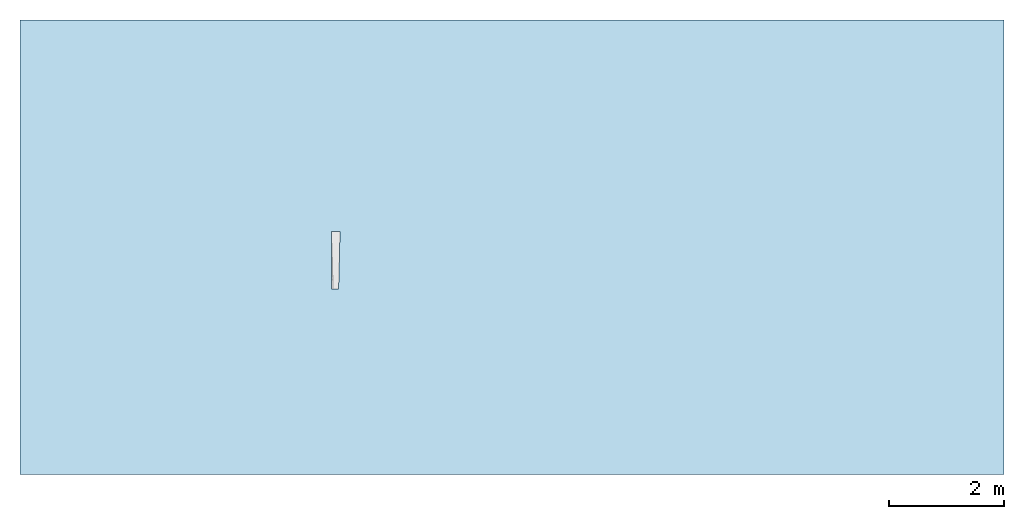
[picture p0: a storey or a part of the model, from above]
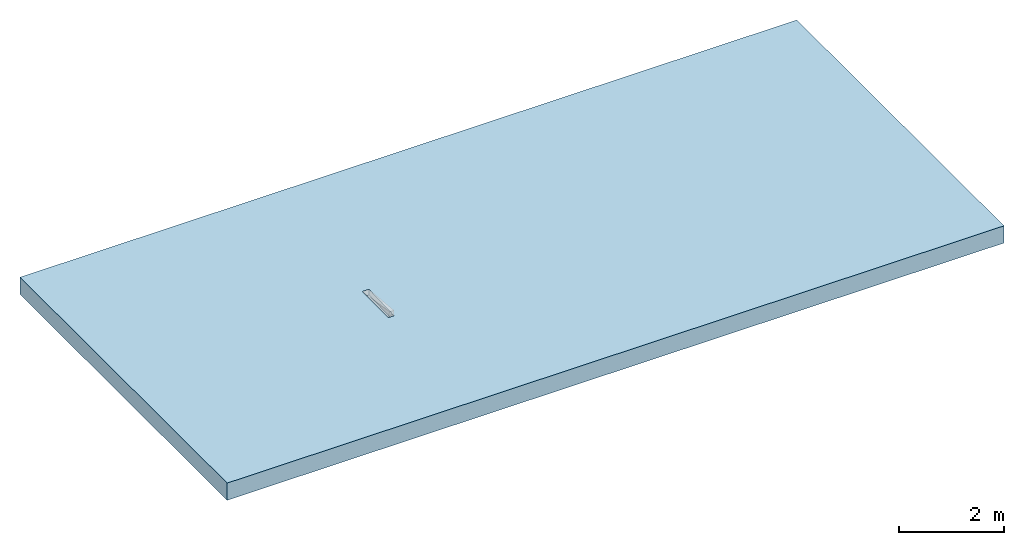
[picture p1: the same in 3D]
Properties of the parts of a building model (IFC2X3)

# File
Description: ViewDefinition [CoordinationView]
File name: 7957 - RH drop kerb - 1000mm LG.ifc
Time: 2013-08-30T17:42:58
Written by: Autodesk Revit 2013
Made in: 20120221_2030(x64)

# IfcProject, Project Number
LongName: Project Name; Phase: Project Status

# IfcSite, Default
RefLatitude: 42, 21, 30, 344238; RefLongitude: -71, -3, -35, -194702; RefElevation: 0 mm

# IfcBuilding
Pset_BuildingCommon - NumberOfStoreys: 1
Other - Project Number: Project Number; Project Status: Project Status; Client Name: Owner; Project Issue Date: Issue Date; Project Address: ## Street City, State Zip; Project Name: Project Name

# IfcBuildingStorey, Level 1
LongName: Level 1; Elevation: 0 mm
Constraints - Elevation Base: 0; Elevation: 0 mm
Graphics - Symbol: M_Level Head - Circle: M_Level Head - Circle; Line Pattern: Center; Line Weight: 1; Symbol at End 2 Default: yes; Color: 0; Symbol at End 1 Default: no
Identity Data - Name: Level 1; Structural: no; Building Story: yes
Dimensions - Computation Height: 0 mm

# IfcBuildingElementProxy: 7957 - RH drop kerb - 1000mm LG, Civil-Drainage-Channel-ACO-KerbDrain-HB255:7957 - RH drop kerb - 1000mm LG:7957 - RH drop kerb - 1000mm LG:754467
In: Level 1
Material: ACO Polymer Concrete.
Phasing - Phase Created: New Construction
Constraints - Moves With Nearby Elements: no; Level: Level: Level 1
Dimensions - Volume: 17724360 mm3; Access Depth: 2000 mm; RH Void Start: -130 mm; LH Void End: -2005 mm; Void Width: 150 mm; Void Length: 1000 mm; Void Depth: -2005 mm; Void Start: -2000 mm; LH Void Start: -2000 mm; RH Hole End: 0 mm
Pset_BuildingElementProxyCommon - Reference: 7957 - RH drop kerb - 1000mm LG
Materials and Finishes - Channel Material: Vienite® Synthetic Resin Concrete; End Cap Material: N/A; End Cap Colour: N/A; Access Cover/Frame Material: N/A; Access Cover/Frame Colour: N/A; Access Cover/Frame Finish: N/A; Channel Colour: Grey
General - SerialNumber: 0.000000; TagNumber: 0.000000
Construction - Closing end cap: no; Access Unit: no; HB255 - 1000: no; LH drop kerb: no; RH drop kerb: yes; Centre Stone: no; HB255 - 500: no
Identity Data - Product Page URL: http://www.aco.co.uk/product_detail.php?id=3; Maintenance guidelines: http://www.aco.co.uk/download.php?id=120; e-mail Technical: technical@aco.co.uk; Type Comments: ACO KerbDrain HB255 half battered right-hand drop kerb unit 1000mm long; URL: www.aco.co.uk; Manufacturer: ACO Technologies plc - ACO Water Management Division; e-mail Sales: customersupport@aco.co.uk; Assembly Code: D2040; Model: ACO KerbDrain HB255; Fax: +44 (0)1462 815895; OmniClass Number: 23.70.50.24; Installation guidelines: http://www.aco.co.uk/download.php?id=120; Address: ACO Business Park, Hitchin Road, Shefford, Bedfordshire, United Kingdom SG17 5TE; Product Code: 7957; Assembly Description: Rain Water Drainage; Telephone: +44 (0)1462 816666; Cost: 0; Model Description: Combined kerb and drainage system; Product brochure: http://www.aco.co.uk/download.php?id=120; OmniClass Title: Rainwater Removal; Price: POA - contact ACO
Green Building Properties - End Cap Recyclable: N/A; Access Cover/Frame Recyclable: N/A; Channel Recycled Material Content: 20% minimum; Channel Recyclable: Fully recyclable; End Cap Recycled Material Content: N/A; Access Cover/Frame Recycled Material Content: N/A
Data - Load Class: A 15 - D 400; Hydraulic Performance: http://www.aco.co.uk/download.php?id=120; Product Weight: 38.0 Kg; Installation - Concrete Grade: Refer to brochure; Invert Depth: 235/105mm; ACO Hydraulic Design Software: http://www.acodesign.co.uk; Drainage Slot Intake area: N/A; Channel C.S.A: 0.01 to 0.005m²; Product Dimensions: 1000mm x 125/150mm x 255/130mm (LxWxH); Product Standard: BS EN 1433:2002, CE marked, Kitemarked; Connection Pipe O.D: N/A; Concrete Surround Volume - Load Class A 15 - D 400 - Grass or Asphalt Pavement: N/A; Drainage Slot Width: N/A; Concrete Surround Volume - Load Class A 15 - D 400 - Concrete Pavement: N/A
Other - CreatedBy: www.aco.co.uk; Revision: 1

# IfcOpeningElement: Recess (3)
In: Level 1
Phasing - Phase Created: New Construction
Constraints - Height Offset From Level: 0 mm; Level: Level: Level 1; Related to Mass: no; Room Bounding: yes
Structural - Enable Analytical Model: no; Structural: no
Dimensions - Volume: 54018125000 mm3; Area: 135090000 mm2; Thickness: 400 mm; Perimeter: 50000 mm
Graphics - Coarse Scale Fill Color: 0
Analytical Properties - Absorptance: 0.1; Roughness: 1
Construction - Function: 0; Default Thickness: 400 mm
Materials and Finishes - Structural Material: Plant

# IfcSlab: Floor:Generic Floor - 400mm, Floor:Generic Floor - 400mm:193825
In: Level 1
PredefinedType: FLOOR; Material: Plant 400 mm
Phasing - Phase Created: New Construction
Constraints - Height Offset From Level: 0 mm; Level: Level: Level 1; Related to Mass: no; Room Bounding: yes
Structural - Enable Analytical Model: no; Structural: no
Dimensions - Volume: 54018125000 mm3; Area: 135090000 mm2; Thickness: 400 mm; Perimeter: 50000 mm
Pset_SlabCommon - Reference: Generic Floor - 400mm; IsExternal: no; LoadBearing: yes
Graphics - Coarse Scale Fill Color: 0
Analytical Properties - Absorptance: 0.1; Roughness: 1
Construction - Function: 0; Default Thickness: 400 mm
Materials and Finishes - Structural Material: Plant
